# This Lef is suitable for top metal5 or above.
#
# Lef Name    : FPFLE032K09DA_M5a.lef 
# ==================STATEMENT===================================
# Copyright (c) 2001-2015 Grace Semiconductor Manufacturing Corporation.
# All Rights Reserved.
# Forwarding or copying of this document, in any medium, in whole or 
# in part, or disclosure of its contents, to other than an authorized 
# recipient, is strictly prohibited.
#
# =============IMPORTANT APPLICATION NOTES======================
# M1~ M5 layers Must NOT be used for routing over the IP region. 
# 
# LEF OUT API 
# User Name : davidzhu 
# Date : Tue Feb  3 09:24:22 2015
# 
NAMESCASESENSITIVE ON ;
BUSBITCHARS "[]" ;
DIVIDERCHAR "/" ;
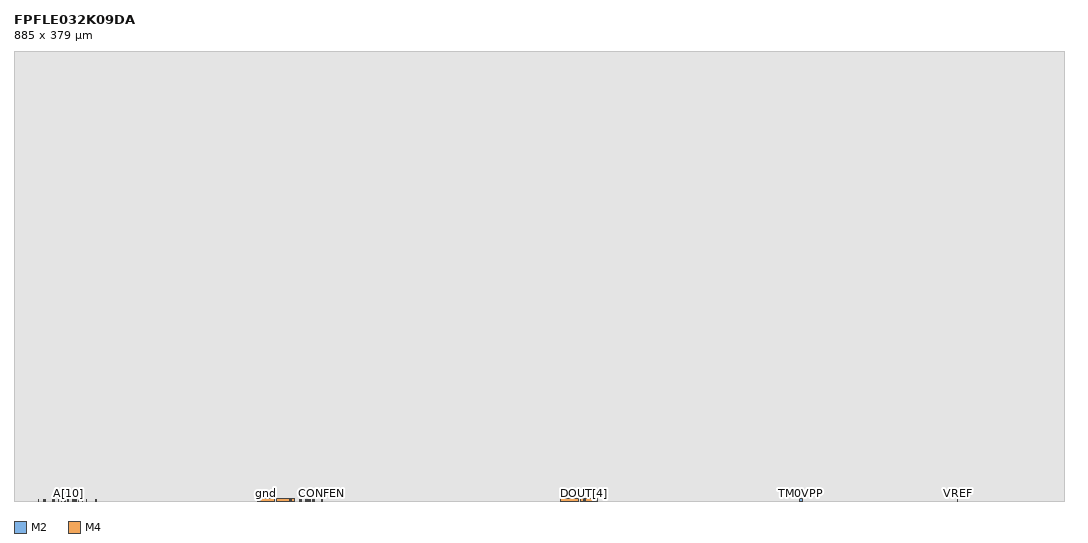
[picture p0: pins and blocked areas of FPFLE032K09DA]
MACRO FPFLE032K09DA
 CLASS BLOCK ;
 FOREIGN FPFLE032K09DA ;
 ORIGIN 0 0 ;
 SIZE 885 BY 379 ;
 SYMMETRY X Y R90 ;
 PIN A[0]
 USE SIGNAL ;
 DIRECTION INPUT ;
 PORT
 LAYER M2 ;
 RECT 26.68 0 26.89 1 ;
 END
 END A[0]
 PIN A[10]
 USE SIGNAL ;
 DIRECTION INPUT ;
 PORT
 LAYER M2 ;
 RECT 45.84 0 46.05 1 ;
 END
 END A[10]
 PIN A[11]
 USE SIGNAL ;
 DIRECTION INPUT ;
 PORT
 LAYER M2 ;
 RECT 49.02 0 49.23 1 ;
 END
 END A[11]
 PIN A[12]
 USE SIGNAL ;
 DIRECTION INPUT ;
 PORT
 LAYER M2 ;
 RECT 54.04 0 54.25 1 ;
 END
 END A[12]
 PIN A[13]
 USE SIGNAL ;
 DIRECTION INPUT ;
 PORT
 LAYER M2 ;
 RECT 51.485 0 51.695 1 ;
 END
 END A[13]
 PIN A[14]
 USE SIGNAL ;
 DIRECTION INPUT ;
 PORT
 LAYER M2 ;
 RECT 50.975 0 51.185 1 ;
 END
 END A[14]
 PIN A[1]
 USE SIGNAL ;
 DIRECTION INPUT ;
 PORT
 LAYER M2 ;
 RECT 32.79 0 33 1 ;
 END
 END A[1]
 PIN A[2]
 USE SIGNAL ;
 DIRECTION INPUT ;
 PORT
 LAYER M2 ;
 RECT 33.63 0 33.84 1 ;
 END
 END A[2]
 PIN A[3]
 USE SIGNAL ;
 DIRECTION INPUT ;
 PORT
 LAYER M2 ;
 RECT 33.21 0 33.42 1 ;
 END
 END A[3]
 PIN A[4]
 USE SIGNAL ;
 DIRECTION INPUT ;
 PORT
 LAYER M2 ;
 RECT 37.29 0 37.5 1 ;
 END
 END A[4]
 PIN A[5]
 USE SIGNAL ;
 DIRECTION INPUT ;
 PORT
 LAYER M2 ;
 RECT 39.88 0 40.09 1 ;
 END
 END A[5]
 PIN A[6]
 USE SIGNAL ;
 DIRECTION INPUT ;
 PORT
 LAYER M2 ;
 RECT 42.525 0 42.735 1 ;
 END
 END A[6]
 PIN A[7]
 USE SIGNAL ;
 DIRECTION INPUT ;
 PORT
 LAYER M2 ;
 RECT 43.16 0 43.37 1 ;
 END
 END A[7]
 PIN A[8]
 USE SIGNAL ;
 DIRECTION INPUT ;
 PORT
 LAYER M2 ;
 RECT 49.65 0 49.86 1 ;
 END
 END A[8]
 PIN A[9]
 USE SIGNAL ;
 DIRECTION INPUT ;
 PORT
 LAYER M2 ;
 RECT 45.21 0 45.42 1 ;
 END
 END A[9]
 PIN BLOCK
 USE SIGNAL ;
 DIRECTION INPUT ;
 PORT
 LAYER M2 ;
 RECT 252.75 0 252.96 1 ;
 END
 END BLOCK
 PIN CEb
 USE SIGNAL ;
 DIRECTION INPUT ;
 PORT
 LAYER M2 ;
 RECT 24.855 0 25.065 1 ;
 END
 END CEb
 PIN CHIP
 USE SIGNAL ;
 DIRECTION INPUT ;
 PORT
 LAYER M2 ;
 RECT 249.73 0 249.94 1 ;
 END
 END CHIP
 PIN CONFEN
 USE SIGNAL ;
 DIRECTION INPUT ;
 PORT
 LAYER M2 ;
 RECT 259.48 0 259.69 1 ;
 END
 END CONFEN
 PIN DEEPPD
 USE SIGNAL ;
 DIRECTION INPUT ;
 PORT
 LAYER M2 ;
 RECT 20.235 0 20.445 1 ;
 END
 END DEEPPD
 PIN DIN[0]
 USE SIGNAL ;
 DIRECTION INPUT ;
 PORT
 LAYER M2 ;
 RECT 241.56 0 241.77 1 ;
 END
 END DIN[0]
 PIN DIN[1]
 USE SIGNAL ;
 DIRECTION INPUT ;
 PORT
 LAYER M2 ;
 RECT 241.05 0 241.26 1 ;
 END
 END DIN[1]
 PIN DIN[2]
 USE SIGNAL ;
 DIRECTION INPUT ;
 PORT
 LAYER M2 ;
 RECT 242.07 0 242.28 1 ;
 END
 END DIN[2]
 PIN DIN[3]
 USE SIGNAL ;
 DIRECTION INPUT ;
 PORT
 LAYER M2 ;
 RECT 245.435 0 245.645 1 ;
 END
 END DIN[3]
 PIN DIN[4]
 USE SIGNAL ;
 DIRECTION INPUT ;
 PORT
 LAYER M2 ;
 RECT 246.455 0 246.665 1 ;
 END
 END DIN[4]
 PIN DIN[5]
 USE SIGNAL ;
 DIRECTION INPUT ;
 PORT
 LAYER M2 ;
 RECT 245.945 0 246.155 1 ;
 END
 END DIN[5]
 PIN DIN[6]
 USE SIGNAL ;
 DIRECTION INPUT ;
 PORT
 LAYER M2 ;
 RECT 246.965 0 247.175 1 ;
 END
 END DIN[6]
 PIN DIN[7]
 USE SIGNAL ;
 DIRECTION INPUT ;
 PORT
 LAYER M2 ;
 RECT 248.2 0 248.41 1 ;
 END
 END DIN[7]
 PIN DOUT[0]
 USE SIGNAL ;
 DIRECTION OUTPUT ;
 PORT
 LAYER M2 ;
 RECT 232.35 0 232.56 1 ;
 END
 END DOUT[0]
 PIN DOUT[1]
 USE SIGNAL ;
 DIRECTION OUTPUT ;
 PORT
 LAYER M2 ;
 RECT 232.865 0 233.075 1 ;
 END
 END DOUT[1]
 PIN DOUT[2]
 USE SIGNAL ;
 DIRECTION OUTPUT ;
 PORT
 LAYER M2 ;
 RECT 233.375 0 233.585 1 ;
 END
 END DOUT[2]
 PIN DOUT[3]
 USE SIGNAL ;
 DIRECTION OUTPUT ;
 PORT
 LAYER M2 ;
 RECT 233.885 0 234.095 1 ;
 END
 END DOUT[3]
 PIN DOUT[4]
 USE SIGNAL ;
 DIRECTION OUTPUT ;
 PORT
 LAYER M2 ;
 RECT 480 0 480.21 1 ;
 END
 END DOUT[4]
 PIN DOUT[5]
 USE SIGNAL ;
 DIRECTION OUTPUT ;
 PORT
 LAYER M2 ;
 RECT 480.51 0 480.72 1 ;
 END
 END DOUT[5]
 PIN DOUT[6]
 USE SIGNAL ;
 DIRECTION OUTPUT ;
 PORT
 LAYER M2 ;
 RECT 481.02 0 481.23 1 ;
 END
 END DOUT[6]
 PIN DOUT[7]
 USE SIGNAL ;
 DIRECTION OUTPUT ;
 PORT
 LAYER M2 ;
 RECT 481.53 0 481.74 1 ;
 END
 END DOUT[7]
 PIN ERASE
 USE SIGNAL ;
 DIRECTION INPUT ;
 PORT
 LAYER M2 ;
 RECT 249.22 0 249.43 1 ;
 END
 END ERASE
 PIN NVR
 USE SIGNAL ;
 DIRECTION INPUT ;
 PORT
 LAYER M2 ;
 RECT 57.665 0 57.875 1 ;
 END
 END NVR
 PIN OEb
 USE SIGNAL ;
 DIRECTION INPUT ;
 PORT
 LAYER M2 ;
 RECT 25.875 0 26.085 1 ;
 END
 END OEb
 PIN PORb
 USE SIGNAL ;
 DIRECTION INPUT ;
 PORT
 LAYER M2 ;
 RECT 251.22 0 251.43 1 ;
 END
 END PORb
 PIN PROG
 USE SIGNAL ;
 DIRECTION INPUT ;
 PORT
 LAYER M2 ;
 RECT 258.97 0 259.18 1 ;
 END
 END PROG
 PIN PROG2
 USE SIGNAL ;
 DIRECTION INPUT ;
 PORT
 LAYER M2 ;
 RECT 252.24 0 252.45 1 ;
 END
 END PROG2
 PIN RDN
 USE SIGNAL ;
 DIRECTION INPUT ;
 PORT
 LAYER M2 ;
 RECT 68.905 0 69.115 1 ;
 END
 END RDN
 PIN TM0VPP
 USE SIGNAL ;
 DIRECTION INOUT ;
 PORT
 LAYER M2 ;
 RECT 661.965 0 664.965 2 ;
 END
 END TM0VPP
 PIN TMEN
 USE SIGNAL ;
 DIRECTION INPUT ;
 PORT
 LAYER M2 ;
 RECT 251.73 0 251.94 1 ;
 END
 END TMEN
 PIN VMON1
 USE SIGNAL ;
 DIRECTION INPUT ;
 PORT
 LAYER M2 ;
 RECT 51.995 0 52.205 1 ;
 END
 END VMON1
 PIN VMON2
 USE SIGNAL ;
 DIRECTION INPUT ;
 PORT
 LAYER M2 ;
 RECT 52.505 0 52.715 1 ;
 END
 END VMON2
 PIN VREAD0
 USE SIGNAL ;
 DIRECTION INPUT ;
 PORT
 LAYER M2 ;
 RECT 61.05 0 61.26 1 ;
 END
 END VREAD0
 PIN VREAD1
 USE SIGNAL ;
 DIRECTION INPUT ;
 PORT
 LAYER M2 ;
 RECT 25.365 0 25.575 1 ;
 END
 END VREAD1
 PIN VREF
 USE SIGNAL ;
 DIRECTION INPUT ;
 PORT
 LAYER M2 ;
 RECT 795.34 0 795.62 1 ;
 END
 END VREF
 PIN WEb
 USE SIGNAL ;
 DIRECTION INPUT ;
 PORT
 LAYER M2 ;
 RECT 248.71 0 248.92 1 ;
 END
 END WEb
 PIN gnd
 USE GROUND ;
 DIRECTION INOUT ;
 PORT
 LAYER M4 ;
 RECT 204.975 0 219.975 2 ;
 END
 PORT
 LAYER M4 ;
 RECT 477.075 0 492.075 2 ;
 END
 END gnd
 PIN vdd
 USE POWER ;
 DIRECTION INOUT ;
 PORT
 LAYER M4 ;
 RECT 221.475 0 236.475 2 ;
 END
 PORT
 LAYER M4 ;
 RECT 460.575 0 475.575 2 ;
 END
 END vdd
 OBS
 LAYER MV1 ;
 RECT 0 0 885 379 ;
 LAYER MV2 ;
 RECT 0 0 885 379 ;
 LAYER MV3 ;
 RECT 0 0 885 379 ;
 LAYER MV4 ;
 RECT 0 0 885 379 ;
 LAYER M1 ;
 RECT 0 0 885 379 ;
 LAYER M2 ;
 RECT 0 0 20.025 1.21 ;
 RECT 0 1.21 661.725 2.24 ;
 RECT 20.655 0 24.645 1.21 ;
 RECT 26.295 0 26.47 1.21 ;
 RECT 27.1 0 32.58 1.21 ;
 RECT 34.05 0 37.08 1.21 ;
 RECT 37.71 0 39.67 1.21 ;
 RECT 40.3 0 42.315 1.21 ;
 RECT 42.945 0 42.95 1.21 ;
 RECT 43.58 0 45 1.21 ;
 RECT 46.26 0 48.81 1.21 ;
 RECT 50.07 0 50.765 1.21 ;
 RECT 52.925 0 53.83 1.21 ;
 RECT 54.46 0 57.455 1.21 ;
 RECT 58.085 0 60.84 1.21 ;
 RECT 61.47 0 68.695 1.21 ;
 RECT 69.325 0 232.14 1.21 ;
 RECT 234.305 0 240.84 1.21 ;
 RECT 242.49 0 245.225 1.21 ;
 RECT 247.385 0 247.99 1.21 ;
 RECT 250.15 0 251.01 1.21 ;
 RECT 253.17 0 258.76 1.21 ;
 RECT 259.9 0 479.79 1.21 ;
 RECT 481.95 0 661.725 1.21 ;
 RECT 665.205 1.21 885 2.24 ;
 RECT 0 2.24 885 379 ;
 RECT 665.205 0 795.13 1.21 ;
 RECT 795.83 0 885 1.21 ;
 LAYER M3 ;
 RECT 0 0 885 379 ;
 LAYER M4 ;
 RECT 0 0 204.375 2.6 ;
 RECT 0 2.6 885 379 ;
 RECT 237.075 0 459.975 2.6 ;
 RECT 220.575 0 220.875 2.6 ;
 RECT 476.175 0 476.475 2.6 ;
 RECT 492.675 0 885 2.6 ;
 LAYER M5 ;
 RECT 0 0 885 379 ;
 END
END FPFLE032K09DA

END LIBRARY
